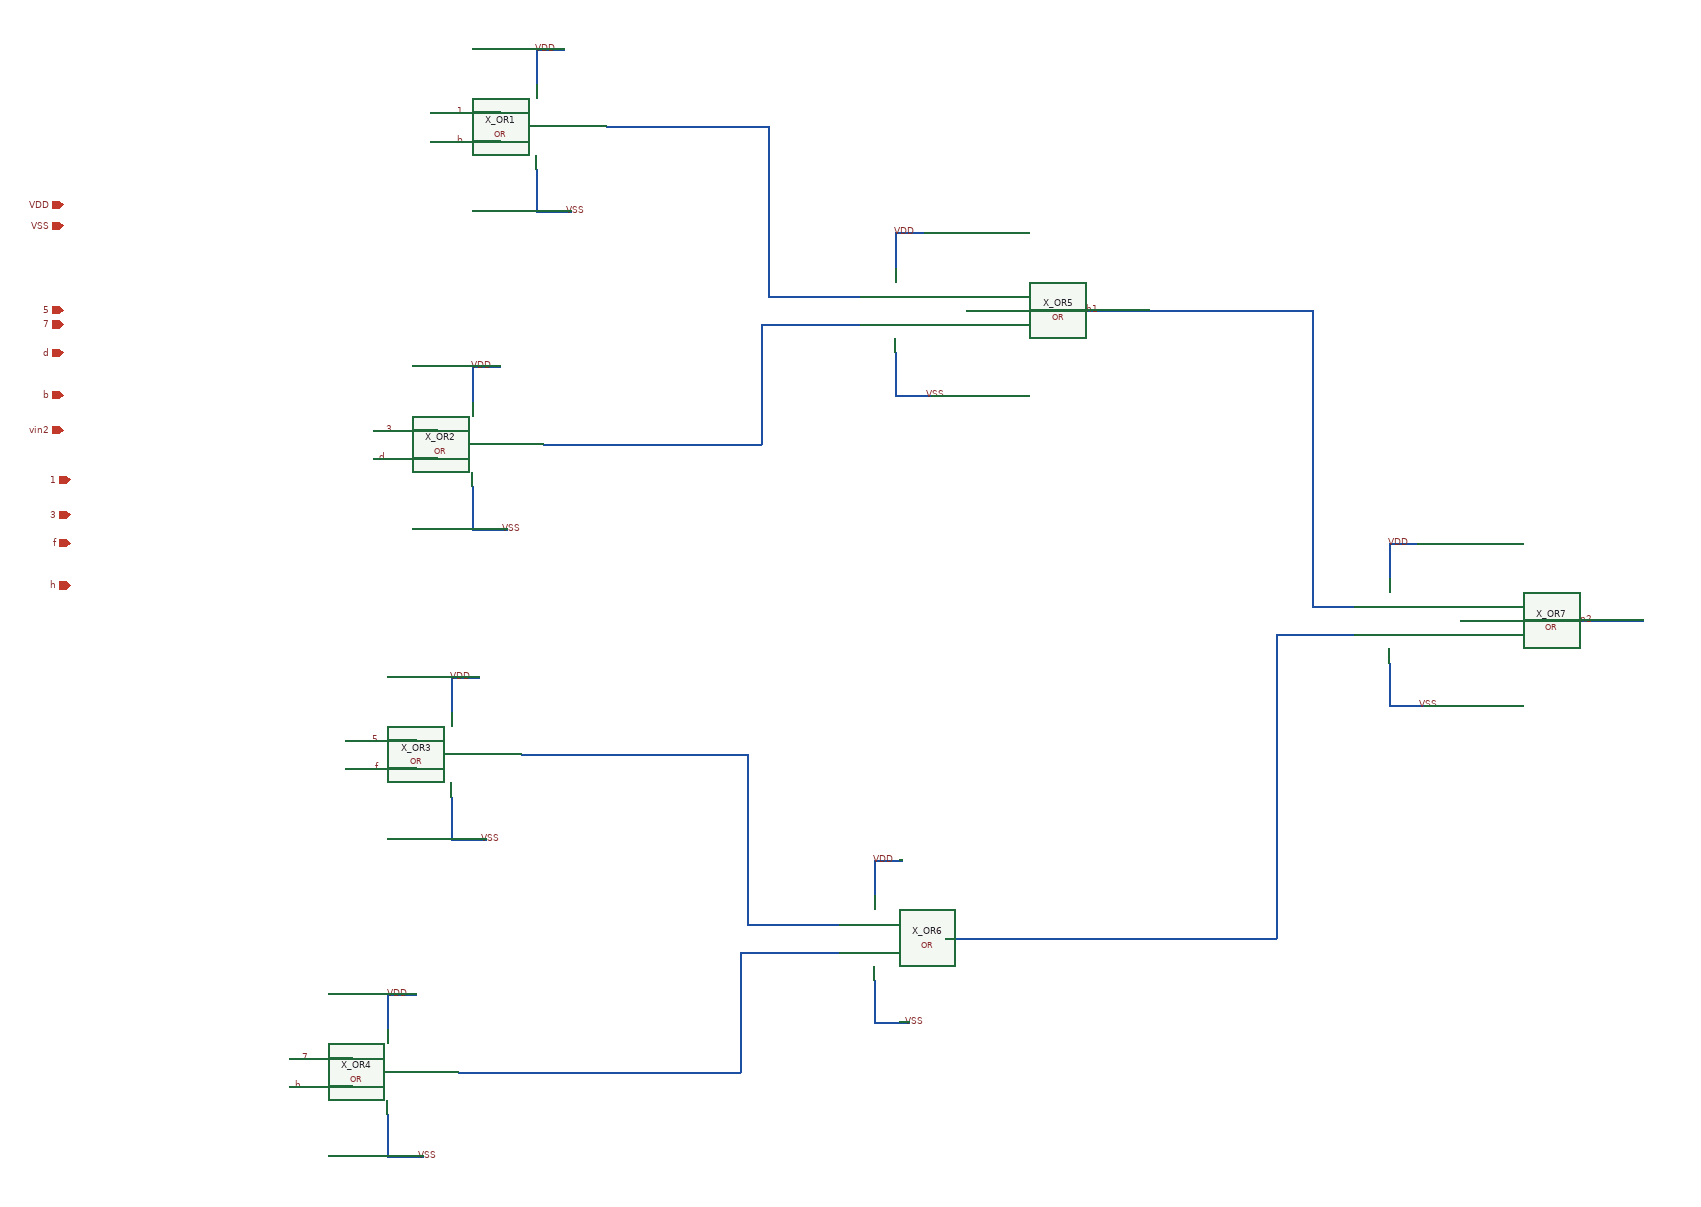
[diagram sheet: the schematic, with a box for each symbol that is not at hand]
v {xschem version=3.0.0 file_version=1.2 }
G {}
K {}
V {}
S {}
E {}
N -310 -1100 -220 -1100 {
lab=#net1}
N -310 -650 -220 -650 {
lab=#net2}
N -120 -860 10 -860 {
lab=#net1}
N -120 -1100 -120 -860 {
lab=#net1}
N -220 -1100 -120 -1100 {
lab=#net1}
N -130 -820 10 -820 {
lab=#net2}
N -130 -820 -130 -650 {
lab=#net2}
N -220 -650 -130 -650 {
lab=#net2}
N 290 -840 420 -840 {
lab=ph1}
N -600 -1120 -500 -1120 {
lab=1}
N -600 -1080 -500 -1080 {
lab=b}
N -680 -670 -590 -670 {
lab=3}
N -680 -630 -590 -630 {
lab=d}
N -340 -210 -250 -210 {
lab=#net3}
N -340 240 -250 240 {
lab=#net4}
N -150 30 -20 30 {
lab=#net3}
N -150 -210 -150 30 {
lab=#net3}
N -250 -210 -150 -210 {
lab=#net3}
N -160 70 -20 70 {
lab=#net4}
N -160 70 -160 240 {
lab=#net4}
N -250 240 -160 240 {
lab=#net4}
N 350 50 480 50 {
lab=#net5}
N -720 -230 -620 -230 {
lab=5}
N -720 -190 -620 -190 {
lab=f}
N -800 220 -710 220 {
lab=7}
N -800 260 -710 260 {
lab=h}
N 990 -400 1120 -400 {
lab=vin2}
N 410 -840 650 -840 {
lab=ph1}
N 650 -840 650 -420 {
lab=ph1}
N 650 -420 710 -420 {
lab=ph1}
N 480 50 600 50 {
lab=#net5}
N 600 -370 600 50 {
lab=#net5}
N -350 -1100 -310 -1100 {
lab=#net1}
N -450 -1210 -450 -1160 {
lab=VDD}
N -450 -1210 -410 -1210 {
lab=VDD}
N -450 -1040 -450 -980 {
lab=VSS}
N -450 -980 -400 -980 {
lab=VSS}
N -400 -650 -310 -650 {
lab=#net2}
N -440 -650 -400 -650 {
lab=#net2}
N -540 -760 -540 -710 {
lab=VDD}
N -540 -760 -500 -760 {
lab=VDD}
N -540 -590 -540 -530 {
lab=VSS}
N -540 -530 -490 -530 {
lab=VSS}
N -430 -210 -340 -210 {
lab=#net3}
N -470 -210 -430 -210 {
lab=#net3}
N -570 -320 -570 -270 {
lab=VDD}
N -570 -320 -530 -320 {
lab=VDD}
N -570 -150 -570 -90 {
lab=VSS}
N -570 -90 -520 -90 {
lab=VSS}
N -430 240 -340 240 {
lab=#net4}
N -520 240 -430 240 {
lab=#net4}
N -560 240 -520 240 {
lab=#net4}
N -660 130 -660 180 {
lab=VDD}
N -660 130 -620 130 {
lab=VDD}
N -660 300 -660 360 {
lab=VSS}
N -660 360 -610 360 {
lab=VSS}
N 200 -840 290 -840 {
lab=ph1}
N 160 -840 200 -840 {
lab=ph1}
N 60 -950 60 -900 {
lab=VDD}
N 60 -950 100 -950 {
lab=VDD}
N 60 -780 60 -720 {
lab=VSS}
N 60 -720 110 -720 {
lab=VSS}
N 260 50 350 50 {
lab=#net5}
N 170 50 260 50 {
lab=#net5}
N 130 50 170 50 {
lab=#net5}
N 30 -60 30 -10 {
lab=VDD}
N 30 -60 70 -60 {
lab=VDD}
N 30 110 30 170 {
lab=VSS}
N 30 170 80 170 {
lab=VSS}
N 900 -400 990 -400 {
lab=vin2}
N 860 -400 900 -400 {
lab=vin2}
N 760 -510 760 -460 {
lab=VDD}
N 760 -510 800 -510 {
lab=VDD}
N 760 -340 760 -280 {
lab=VSS}
N 760 -280 810 -280 {
lab=VSS}
N 600 -380 710 -380 {
lab=#net5}
N 600 -380 600 -370 {
lab=#net5}
C {devices/lab_wire.sym} -550 -1120 0 0 {name=l178 sig_type=std_logic lab=1}
C {devices/lab_wire.sym} -550 -1080 0 0 {name=l179 sig_type=std_logic lab=b}
C {devices/lab_wire.sym} -650 -670 0 0 {name=l180 sig_type=std_logic lab=3}
C {devices/lab_wire.sym} -660 -630 0 0 {name=l181 sig_type=std_logic lab=d}
C {devices/lab_wire.sym} 350 -840 0 0 {name=l182 sig_type=std_logic lab=ph1}
C {devices/lab_wire.sym} -670 -230 0 0 {name=l195 sig_type=std_logic lab=5}
C {devices/lab_wire.sym} -670 -190 0 0 {name=l196 sig_type=std_logic lab=f}
C {devices/lab_wire.sym} -770 220 0 0 {name=l197 sig_type=std_logic lab=7}
C {devices/lab_wire.sym} -780 260 0 0 {name=l198 sig_type=std_logic lab=h}
C {devices/lab_wire.sym} 1050 -400 0 0 {name=l216 sig_type=std_logic lab=vin2}
C {devices/lab_wire.sym} -420 -1210 0 0 {name=l4 sig_type=std_logic lab=VDD}
C {devices/lab_wire.sym} -410 -980 0 1 {name=l14 sig_type=std_logic lab=VSS}
C {DC_DC_Converter/Delay_block_revised/OR_GATE/OR.sym} -520 -1030 0 0 {name=X_OR1}
C {devices/lab_wire.sym} -510 -760 0 0 {name=l24 sig_type=std_logic lab=VDD}
C {devices/lab_wire.sym} -500 -530 0 1 {name=l34 sig_type=std_logic lab=VSS}
C {DC_DC_Converter/Delay_block_revised/OR_GATE/OR.sym} -610 -580 0 0 {name=X_OR2}
C {devices/lab_wire.sym} -540 -320 0 0 {name=l41 sig_type=std_logic lab=VDD}
C {devices/lab_wire.sym} -530 -90 0 1 {name=l44 sig_type=std_logic lab=VSS}
C {DC_DC_Converter/Delay_block_revised/OR_GATE/OR.sym} -640 -140 0 0 {name=X_OR3}
C {devices/lab_wire.sym} -630 130 0 0 {name=l46 sig_type=std_logic lab=VDD}
C {devices/lab_wire.sym} -620 360 0 1 {name=l80 sig_type=std_logic lab=VSS}
C {DC_DC_Converter/Delay_block_revised/OR_GATE/OR.sym} -730 310 0 0 {name=X_OR4}
C {devices/lab_wire.sym} 90 -950 0 0 {name=l81 sig_type=std_logic lab=VDD}
C {devices/lab_wire.sym} 100 -720 0 1 {name=l82 sig_type=std_logic lab=VSS}
C {DC_DC_Converter/Delay_block_revised/OR_GATE/OR.sym} -10 -770 0 0 {name=X_OR5}
C {devices/lab_wire.sym} 60 -60 0 0 {name=l85 sig_type=std_logic lab=VDD}
C {devices/lab_wire.sym} 70 170 0 1 {name=l92 sig_type=std_logic lab=VSS}
C {DC_DC_Converter/Delay_block_revised/OR_GATE/OR.sym} -40 120 0 0 {name=X_OR6}
C {devices/lab_wire.sym} 790 -510 0 0 {name=l83 sig_type=std_logic lab=VDD}
C {devices/lab_wire.sym} 800 -280 0 1 {name=l84 sig_type=std_logic lab=VSS}
C {DC_DC_Converter/Delay_block_revised/OR_GATE/OR.sym} 690 -330 0 0 {name=X_OR7}
C {devices/iopin.sym} -1120 -990 0 0 {name=p1 lab=VDD}
C {devices/iopin.sym} -1120 -960 0 0 {name=p2 lab=VSS}
C {devices/iopin.sym} -1120 -840 0 0 {name=p6 lab=5}
C {devices/iopin.sym} -1120 -820 0 0 {name=p7 lab=7}
C {devices/iopin.sym} -1120 -780 0 0 {name=p8 lab=d}
C {devices/iopin.sym} -1120 -720 0 0 {name=p9 lab=b}
C {devices/iopin.sym} -1120 -670 0 0 {name=p10 lab=vin2}
C {devices/iopin.sym} -1110 -600 0 0 {name=p11 lab=1}
C {devices/iopin.sym} -1110 -550 0 0 {name=p12 lab=3}
C {devices/iopin.sym} -1110 -510 0 0 {name=p3 lab=f}
C {devices/iopin.sym} -1110 -450 0 0 {name=p4 lab=h}
